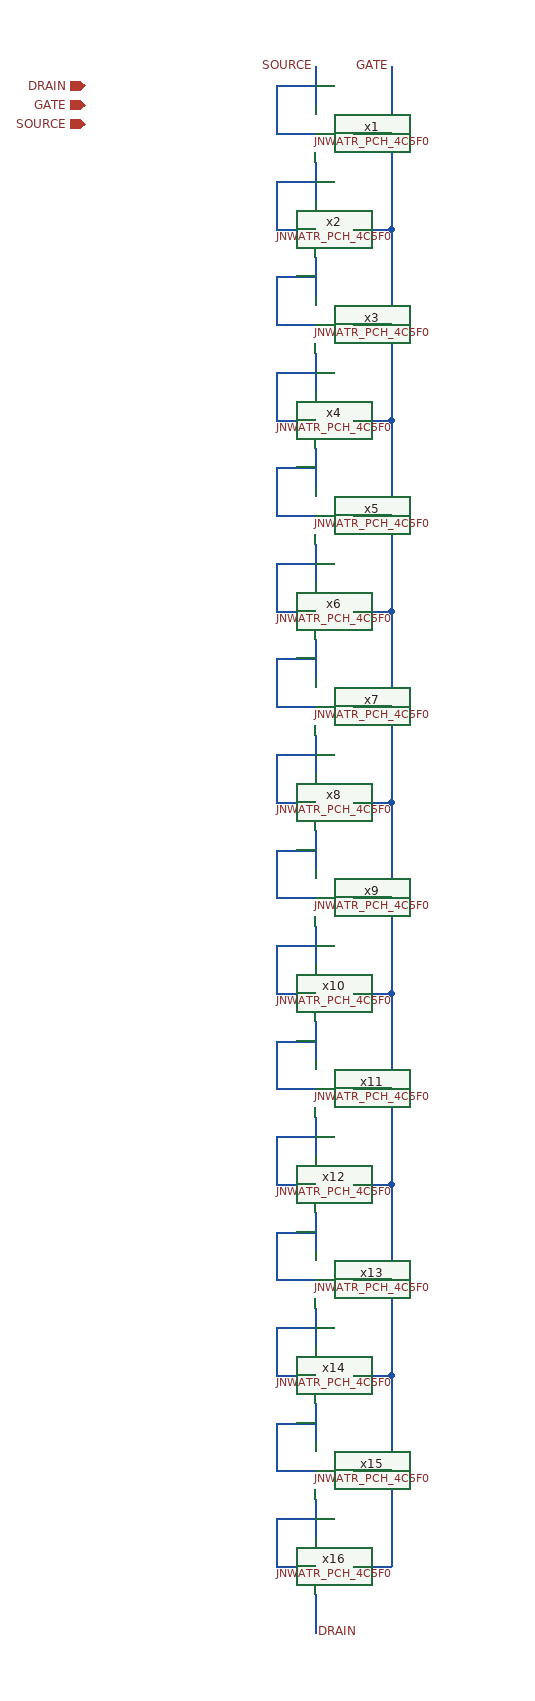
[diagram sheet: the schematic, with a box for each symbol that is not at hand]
v {xschem version=3.4.6 file_version=1.2}
G {}
K {}
V {}
S {}
E {}
N 1720 390 1760 390 {lab=GATE}
N 1720 490 1760 490 {lab=GATE}
N 1640 490 1680 490 {lab=#net1}
N 1640 390 1680 390 {lab=SOURCE}
N 1640 340 1640 390 {lab=SOURCE}
N 1640 340 1680 340 {lab=SOURCE}
N 1640 440 1640 490 {lab=#net1}
N 1640 440 1680 440 {lab=#net1}
N 1680 420 1680 460 {lab=#net1}
N 1680 320 1680 360 {lab=SOURCE}
N 1760 320 1760 490 {lab=GATE}
N 1720 590 1760 590 {lab=GATE}
N 1720 690 1760 690 {lab=GATE}
N 1640 690 1680 690 {lab=#net2}
N 1640 590 1680 590 {lab=#net3}
N 1640 540 1640 590 {lab=#net3}
N 1640 540 1680 540 {lab=#net3}
N 1640 640 1640 690 {lab=#net2}
N 1640 640 1680 640 {lab=#net2}
N 1680 620 1680 660 {lab=#net2}
N 1680 520 1680 560 {lab=#net3}
N 1760 490 1760 690 {lab=GATE}
N 1720 790 1760 790 {lab=GATE}
N 1720 890 1760 890 {lab=GATE}
N 1640 890 1680 890 {lab=#net4}
N 1640 790 1680 790 {lab=#net5}
N 1640 740 1640 790 {lab=#net5}
N 1640 740 1680 740 {lab=#net5}
N 1640 840 1640 890 {lab=#net4}
N 1640 840 1680 840 {lab=#net4}
N 1680 820 1680 860 {lab=#net4}
N 1680 720 1680 760 {lab=#net5}
N 1760 690 1760 890 {lab=GATE}
N 1720 990 1760 990 {lab=GATE}
N 1720 1090 1760 1090 {lab=GATE}
N 1640 1090 1680 1090 {lab=#net6}
N 1640 990 1680 990 {lab=#net7}
N 1640 940 1640 990 {lab=#net7}
N 1640 940 1680 940 {lab=#net7}
N 1640 1040 1640 1090 {lab=#net6}
N 1640 1040 1680 1040 {lab=#net6}
N 1680 1020 1680 1060 {lab=#net6}
N 1680 920 1680 960 {lab=#net7}
N 1760 890 1760 1090 {lab=GATE}
N 1720 1190 1760 1190 {lab=GATE}
N 1720 1290 1760 1290 {lab=GATE}
N 1640 1290 1680 1290 {lab=#net8}
N 1640 1190 1680 1190 {lab=#net9}
N 1640 1140 1640 1190 {lab=#net9}
N 1640 1140 1680 1140 {lab=#net9}
N 1640 1240 1640 1290 {lab=#net8}
N 1640 1240 1680 1240 {lab=#net8}
N 1680 1220 1680 1260 {lab=#net8}
N 1680 1120 1680 1160 {lab=#net9}
N 1760 1090 1760 1290 {lab=GATE}
N 1720 1390 1760 1390 {lab=GATE}
N 1720 1490 1760 1490 {lab=GATE}
N 1640 1490 1680 1490 {lab=#net10}
N 1640 1390 1680 1390 {lab=#net11}
N 1640 1340 1640 1390 {lab=#net11}
N 1640 1340 1680 1340 {lab=#net11}
N 1640 1440 1640 1490 {lab=#net10}
N 1640 1440 1680 1440 {lab=#net10}
N 1680 1420 1680 1460 {lab=#net10}
N 1680 1320 1680 1360 {lab=#net11}
N 1760 1290 1760 1490 {lab=GATE}
N 1720 1590 1760 1590 {lab=GATE}
N 1720 1690 1760 1690 {lab=GATE}
N 1640 1690 1680 1690 {lab=#net12}
N 1640 1590 1680 1590 {lab=#net13}
N 1640 1540 1640 1590 {lab=#net13}
N 1640 1540 1680 1540 {lab=#net13}
N 1640 1640 1640 1690 {lab=#net12}
N 1640 1640 1680 1640 {lab=#net12}
N 1680 1620 1680 1660 {lab=#net12}
N 1680 1520 1680 1560 {lab=#net13}
N 1760 1490 1760 1690 {lab=GATE}
N 1720 1790 1760 1790 {lab=GATE}
N 1720 1890 1760 1890 {lab=GATE}
N 1640 1890 1680 1890 {lab=#net14}
N 1640 1790 1680 1790 {lab=#net15}
N 1640 1740 1640 1790 {lab=#net15}
N 1640 1740 1680 1740 {lab=#net15}
N 1640 1840 1640 1890 {lab=#net14}
N 1640 1840 1680 1840 {lab=#net14}
N 1680 1820 1680 1860 {lab=#net14}
N 1680 1720 1680 1760 {lab=#net15}
N 1760 1690 1760 1890 {lab=GATE}
N 1680 1920 1680 1960 {lab=DRAIN}
C {JNW_ATR_SKY130A/JNWATR_PCH_4C5F0.sym} 1720 390 0 1 {name=x1 }
C {JNW_ATR_SKY130A/JNWATR_PCH_4C5F0.sym} 1720 490 0 1 {name=x2 }
C {JNW_ATR_SKY130A/JNWATR_PCH_4C5F0.sym} 1720 590 0 1 {name=x3 }
C {JNW_ATR_SKY130A/JNWATR_PCH_4C5F0.sym} 1720 690 0 1 {name=x4 }
C {JNW_ATR_SKY130A/JNWATR_PCH_4C5F0.sym} 1720 790 0 1 {name=x5 }
C {JNW_ATR_SKY130A/JNWATR_PCH_4C5F0.sym} 1720 890 0 1 {name=x6 }
C {JNW_ATR_SKY130A/JNWATR_PCH_4C5F0.sym} 1720 990 0 1 {name=x7 }
C {JNW_ATR_SKY130A/JNWATR_PCH_4C5F0.sym} 1720 1090 0 1 {name=x8 }
C {JNW_ATR_SKY130A/JNWATR_PCH_4C5F0.sym} 1720 1190 0 1 {name=x9 }
C {JNW_ATR_SKY130A/JNWATR_PCH_4C5F0.sym} 1720 1290 0 1 {name=x10 }
C {JNW_ATR_SKY130A/JNWATR_PCH_4C5F0.sym} 1720 1390 0 1 {name=x11 }
C {JNW_ATR_SKY130A/JNWATR_PCH_4C5F0.sym} 1720 1490 0 1 {name=x12 }
C {JNW_ATR_SKY130A/JNWATR_PCH_4C5F0.sym} 1720 1590 0 1 {name=x13 }
C {JNW_ATR_SKY130A/JNWATR_PCH_4C5F0.sym} 1720 1690 0 1 {name=x14 }
C {JNW_ATR_SKY130A/JNWATR_PCH_4C5F0.sym} 1720 1790 0 1 {name=x15 }
C {JNW_ATR_SKY130A/JNWATR_PCH_4C5F0.sym} 1720 1890 0 1 {name=x16 }
C {devices/lab_pin.sym} 1680 320 0 0 {name=p1 sig_type=std_logic lab=SOURCE}
C {devices/lab_pin.sym} 1680 1960 0 1 {name=p3 sig_type=std_logic lab=DRAIN}
C {devices/lab_pin.sym} 1760 320 0 0 {name=p2 sig_type=std_logic lab=GATE}
C {devices/iopin.sym} 1440 340 0 0 {name=p0 lab=DRAIN}
C {devices/iopin.sym} 1440 360 0 0 {name=p4 lab=GATE}
C {devices/iopin.sym} 1440 380 0 0 {name=p5 lab=SOURCE}
